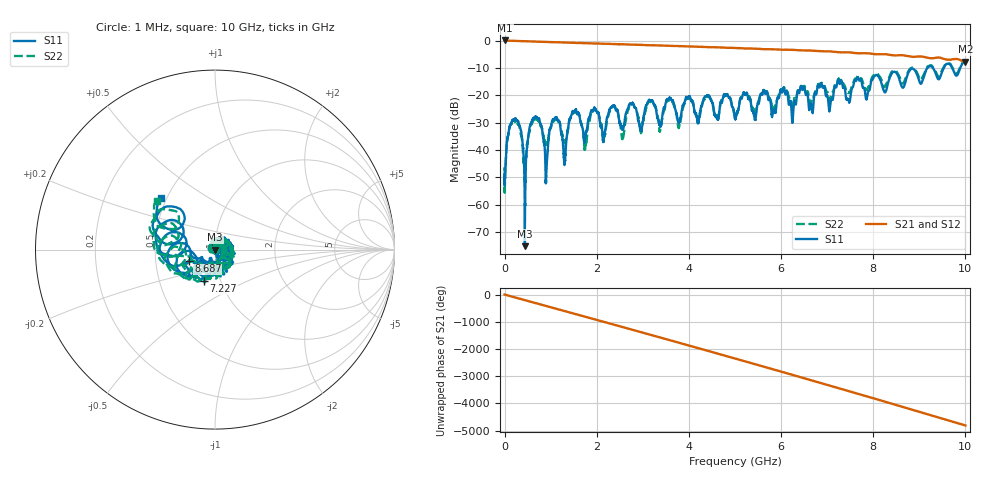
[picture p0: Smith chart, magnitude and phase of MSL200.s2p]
! 3/21/2017 9:37:04 AM
! F:\HUSERTL_20170321\MSL200.S2P
! CHANNEL.1
! TR.MEASUREMENT
! CORRECTED.DATA
# GHZ S RI R 50.0
! FREQ.GHZ  S11RE  S11IM  S21RE  S21IM  S12RE  S12IM  S22RE  S22IM
!; PortSelection: Port_13
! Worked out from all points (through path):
!   10000 points, 1 MHz to 10 GHz, reference 50 ohm
!   highest |S21| = 0.04 dB at 10 MHz (marker M1); lowest = -7.8 dB at 10 GHz (marker M2)
!   group delay of S21, straight-line fit = 1.33 ns
!   lowest |S11| = -75.2 dB at 441 MHz (marker M3), VSWR 1.00, Z = 50 - j0.0167 ohm
!   |S11| at or under -10 dB: start of sweep to 9.175 GHz; 9.294 GHz to 9.532 GHz (237.8 MHz wide, 2.53 % of centre); 9.713 GHz to 9.888 GHz (175 MHz wide, 1.79 % of centre)
!   |S22| runs from -55.7 to -7.5 dB; largest |S21 - S12| = 0.045
!   S11 on the Smith chart (normalised r, x): 1 MHz: 1.01, +0.00; 7.227 GHz: 0.84, -0.30; 8.687 GHz: 0.74, -0.10; 10 GHz: 0.47, +0.33
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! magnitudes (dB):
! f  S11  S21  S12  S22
! 1 MHz  -50.8  0.0  0.0  -53.6
! 10 MHz  -50.4  0.0  0.0  -48.8
! 212 MHz  -28.9  -0.1  -0.2  -29.3
! 441 MHz  -75.2  -0.2  -0.3  -51.0
! 647 MHz  -28.4  -0.4  -0.4  -29.0
! 897 MHz  -50.9  -0.5  -0.5  -38.1
! 1.079 GHz  -28.8  -0.6  -0.6  -29.3
! 1.297 GHz  -44.5  -0.7  -0.7  -37.2
! 1.483 GHz  -25.8  -0.8  -0.8  -26.4
! 1.668 GHz  -30.8  -0.9  -0.9  -30.7
! 3.164 GHz  -21.9  -1.7  -1.7  -22.5
! 3.334 GHz  -28.8  -1.8  -1.8  -28.9
! 3.981 GHz  -21.0  -2.1  -2.2  -21.2
! 5.001 GHz  -28.6  -2.7  -2.7  -27.3
! 5.22 GHz  -19.9  -2.9  -2.9  -19.4
! 5.416 GHz  -27.4  -3.0  -3.0  -25.6
! 5.649 GHz  -19.1  -3.2  -3.2  -18.7
! 6.667 GHz  -24.4  -3.7  -3.8  -22.1
! 7.227 GHz  -14.7  -4.2  -4.3  -14.9
! 8.334 GHz  -14.7  -5.1  -5.2  -14.0
! 8.687 GHz  -15.9  -5.5  -5.5  -14.4
! 10 GHz  -7.6  -7.8  -7.8  -7.5
